VERSION 5.8 ;
BUSBITCHARS "[]" ;
DIVIDERCHAR "/" ;

PROPERTYDEFINITIONS
MACRO RO_tune4 STRING ;
END PROPERTYDEFINITIONS

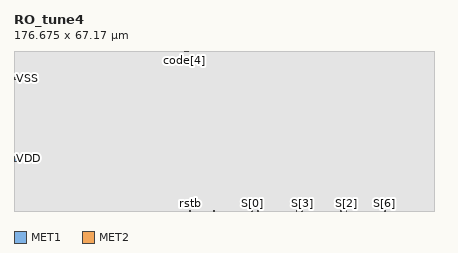
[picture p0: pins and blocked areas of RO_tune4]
MACRO RO_tune4
  CLASS BLOCK ;
  ORIGIN 76.435 85.825 ;
  FOREIGN RO_tune4 -76.435 -85.825 ;
  SIZE 176.675 BY 67.17 ;
  SYMMETRY X Y R90 ;
  PIN code[0]
    DIRECTION INPUT ;
    USE SIGNAL ;
    PORT
      LAYER MET1 ;
        RECT -2.775 -18.885 -2.545 -18.655 ;
    END
  END code[0]
  PIN code[7]
    DIRECTION INPUT ;
    USE SIGNAL ;
    PORT
      LAYER MET1 ;
        RECT -1.805 -18.885 -1.575 -18.655 ;
    END
  END code[7]
  PIN S[0]
    DIRECTION OUTPUT ;
    USE SIGNAL ;
    PORT
      LAYER MET2 ;
        RECT 23.66 -85.825 23.94 -85.545 ;
    END
  END S[0]
  PIN S[7]
    DIRECTION OUTPUT ;
    USE SIGNAL ;
    PORT
      LAYER MET2 ;
        RECT 60.87 -85.825 61.15 -85.545 ;
    END
  END S[7]
  PIN rstb
    DIRECTION INPUT ;
    USE SIGNAL ;
    PORT
      LAYER MET2 ;
        RECT -2.505 -85.825 -2.225 -85.545 ;
    END
  END rstb
  PIN code[1]
    DIRECTION INPUT ;
    USE SIGNAL ;
    PORT
      LAYER MET1 ;
        RECT -3.26 -18.885 -3.03 -18.655 ;
    END
  END code[1]
  PIN code[2]
    DIRECTION INPUT ;
    USE SIGNAL ;
    PORT
      LAYER MET1 ;
        RECT -3.745 -18.885 -3.515 -18.655 ;
    END
  END code[2]
  PIN code[3]
    DIRECTION INPUT ;
    USE SIGNAL ;
    PORT
      LAYER MET1 ;
        RECT -4.23 -18.885 -4 -18.655 ;
    END
  END code[3]
  PIN code[4]
    DIRECTION INPUT ;
    USE SIGNAL ;
    PORT
      LAYER MET1 ;
        RECT -4.715 -18.885 -4.485 -18.655 ;
    END
  END code[4]
  PIN code[5]
    DIRECTION INPUT ;
    USE SIGNAL ;
    PORT
      LAYER MET1 ;
        RECT -5.2 -18.885 -4.97 -18.655 ;
    END
  END code[5]
  PIN code[6]
    DIRECTION INPUT ;
    USE SIGNAL ;
    PORT
      LAYER MET1 ;
        RECT -2.29 -18.885 -2.06 -18.655 ;
    END
  END code[6]
  PIN VDD
    DIRECTION INOUT ;
    USE POWER ;
    PORT
      LAYER MET1 ;
        RECT -76.05 -64.845 -74.06 -62.845 ;
    END
  END VDD
  PIN VSS
    DIRECTION INOUT ;
    USE GROUND ;
    PORT
      LAYER MET1 ;
        RECT -76.215 -30.69 -75.015 -30.43 ;
        RECT -76.215 -30.69 -75.185 -29.67 ;
    END
  END VSS
  PIN S[2]
    DIRECTION OUTPUT ;
    USE SIGNAL ;
    PORT
      LAYER MET2 ;
        RECT 63.25 -85.825 63.53 -85.545 ;
    END
  END S[2]
  PIN S[6]
    DIRECTION OUTPUT ;
    USE SIGNAL ;
    PORT
      LAYER MET2 ;
        RECT 79.475 -85.825 79.755 -85.545 ;
    END
  END S[6]
  PIN S[3]
    DIRECTION OUTPUT ;
    USE SIGNAL ;
    PORT
      LAYER MET2 ;
        RECT 44.645 -85.825 44.925 -85.545 ;
    END
  END S[3]
  PIN S[1]
    DIRECTION OUTPUT ;
    USE SIGNAL ;
    PORT
      LAYER MET2 ;
        RECT 26.04 -85.825 26.32 -85.545 ;
    END
  END S[1]
  PIN S[5]
    DIRECTION OUTPUT ;
    USE SIGNAL ;
    PORT
      LAYER MET2 ;
        RECT 42.265 -85.825 42.545 -85.545 ;
    END
  END S[5]
  PIN S[4]
    DIRECTION OUTPUT ;
    USE SIGNAL ;
    PORT
      LAYER MET2 ;
        RECT 7.435 -85.825 7.715 -85.545 ;
    END
  END S[4]
  PIN vdd!
    DIRECTION INOUT ;
    USE POWER ;
    PORT
      LAYER MET1 ;
        RECT -76.05 -64.845 -74.06 -62.845 ;
    END
  END vdd!
  OBS
    LAYER MET1 ;
      RECT 99.25 -67.175 99.55 -57.125 ;
      RECT 98.13 -67.175 98.43 -57.125 ;
      RECT 97.01 -67.175 97.31 -57.125 ;
      RECT 95.89 -67.175 96.19 -57.125 ;
      RECT 95.76 -67.175 100.24 -66.755 ;
      RECT 99.81 -66.425 100.11 -46.325 ;
      RECT 98.69 -66.425 98.99 -46.325 ;
      RECT 97.57 -66.425 97.87 -46.325 ;
      RECT 96.45 -66.425 96.75 -46.325 ;
      RECT 95.76 -56.795 100.24 -55.955 ;
      RECT 99.25 -55.625 99.55 -35.525 ;
      RECT 98.13 -55.625 98.43 -35.525 ;
      RECT 97.01 -55.625 97.31 -35.525 ;
      RECT 95.89 -55.625 96.19 -35.525 ;
      RECT 95.76 -45.995 100.24 -45.155 ;
      RECT 99.81 -44.825 100.11 -24.725 ;
      RECT 98.69 -44.825 98.99 -24.725 ;
      RECT 97.57 -44.825 97.87 -24.725 ;
      RECT 96.45 -44.825 96.75 -24.725 ;
      RECT 95.76 -35.195 100.24 -34.355 ;
      RECT 95.76 -24.395 100.24 -23.975 ;
      RECT 99.25 -34.025 99.55 -23.975 ;
      RECT 98.13 -34.025 98.43 -23.975 ;
      RECT 97.01 -34.025 97.31 -23.975 ;
      RECT 95.89 -34.025 96.19 -23.975 ;
      RECT -1.805 -60.23 -1.575 -19.485 ;
      RECT -1.83 -60.23 -1.55 -59.85 ;
      RECT -2.29 -55.465 -2.06 -19.485 ;
      RECT -2.315 -55.465 -2.035 -55.085 ;
      RECT -2.775 -50.7 -2.545 -19.485 ;
      RECT -2.8 -50.7 -2.52 -50.32 ;
      RECT -3.26 -45.86 -3.03 -19.485 ;
      RECT -3.285 -45.86 -3.005 -45.48 ;
      RECT -3.745 -41.12 -3.515 -19.485 ;
      RECT -3.77 -41.12 -3.49 -40.74 ;
      RECT -4.23 -36.28 -4 -19.485 ;
      RECT -4.255 -36.28 -3.975 -35.9 ;
      RECT -4.715 -31.515 -4.485 -19.485 ;
      RECT -4.74 -31.515 -4.46 -31.135 ;
      RECT -5.2 -26.725 -4.97 -19.485 ;
      RECT -5.225 -26.725 -4.945 -26.345 ;
      RECT -76.215 -32.35 -75.015 -31.29 ;
      RECT -76.215 -53.845 -75.185 -31.29 ;
      RECT -76.215 -33.49 -22.935 -32.58 ;
      RECT -76.215 -40.685 -21.175 -40.345 ;
      RECT -76.215 -47.265 -21.175 -46.925 ;
      RECT -76.215 -53.845 -21.175 -53.505 ;
      RECT -76.215 -62.09 -75.875 -31.29 ;
      RECT -76.215 -62.09 -5.555 -61.75 ;
      RECT -73.46 -64.845 -0.255 -62.845 ;
      RECT -74.875 -30.2 -48.615 -29.86 ;
      RECT -74.515 -32.35 -74.175 -30.43 ;
    LAYER MET1 SPACING 0.23 ;
      RECT -1.155 -85.825 100.24 -18.655 ;
      RECT -76.435 -29.25 -5.62 -18.655 ;
      RECT -73.64 -85.825 100.24 -19.305 ;
      RECT -74.765 -30.2 100.24 -19.305 ;
      RECT -74.595 -62.425 -5.62 -18.655 ;
      RECT -74.875 -30.2 100.24 -29.86 ;
      RECT -76.435 -62.425 100.24 -31.11 ;
      RECT -76.435 -85.825 100.24 -65.265 ;
    LAYER MET2 ;
      RECT 99.26 -67.175 99.54 -57.125 ;
      RECT 98.14 -67.175 98.42 -57.125 ;
      RECT 97.02 -67.175 97.3 -57.125 ;
      RECT 95.9 -67.175 96.18 -57.125 ;
      RECT 95.76 -67.175 100.24 -66.775 ;
      RECT 99.82 -66.425 100.1 -46.325 ;
      RECT 98.7 -66.425 98.98 -46.325 ;
      RECT 97.58 -66.425 97.86 -46.325 ;
      RECT 96.46 -66.425 96.74 -46.325 ;
      RECT 95.76 -56.775 100.24 -55.975 ;
      RECT 99.26 -55.625 99.54 -35.525 ;
      RECT 98.14 -55.625 98.42 -35.525 ;
      RECT 97.02 -55.625 97.3 -35.525 ;
      RECT 95.9 -55.625 96.18 -35.525 ;
      RECT 95.76 -45.975 100.24 -45.175 ;
      RECT 99.82 -44.825 100.1 -24.725 ;
      RECT 98.7 -44.825 98.98 -24.725 ;
      RECT 97.58 -44.825 97.86 -24.725 ;
      RECT 96.46 -44.825 96.74 -24.725 ;
      RECT 95.76 -35.175 100.24 -34.375 ;
      RECT 95.76 -24.375 100.24 -23.975 ;
      RECT 99.26 -34.025 99.54 -23.975 ;
      RECT 98.14 -34.025 98.42 -23.975 ;
      RECT 97.02 -34.025 97.3 -23.975 ;
      RECT 95.9 -34.025 96.18 -23.975 ;
      RECT 79.445 -84.49 79.785 -80.11 ;
      RECT 79.475 -84.945 79.755 -80.11 ;
      RECT 63.22 -84.49 63.56 -80.11 ;
      RECT 63.25 -84.945 63.53 -80.11 ;
      RECT 60.84 -84.49 61.18 -80.11 ;
      RECT 60.87 -84.945 61.15 -80.11 ;
      RECT 44.615 -84.49 44.955 -80.11 ;
      RECT 44.645 -84.945 44.925 -80.11 ;
      RECT 42.235 -84.49 42.575 -80.11 ;
      RECT 42.265 -84.945 42.545 -80.11 ;
      RECT -31 -22.655 34.925 -18.655 ;
      RECT 30.925 -24.305 34.925 -18.655 ;
      RECT -31 -23.7 -27 -18.655 ;
      RECT 26.01 -84.49 26.35 -80.11 ;
      RECT 26.04 -84.945 26.32 -80.11 ;
      RECT 23.63 -84.49 23.97 -80.11 ;
      RECT 23.66 -84.945 23.94 -80.11 ;
      RECT -2.505 -77.39 12.715 -77.11 ;
      RECT 12.435 -79.025 12.715 -77.11 ;
      RECT -2.505 -84.945 -2.225 -77.11 ;
      RECT -2.59 -83.595 -2.13 -82.095 ;
      RECT 7.405 -84.49 7.745 -80.11 ;
      RECT 7.435 -84.945 7.715 -80.11 ;
      RECT 82.44 -85.55 83.44 -68.935 ;
      RECT -5.12 -85.825 -3.12 -60.855 ;
      RECT -74.515 -44.49 -74.175 -23.065 ;
    LAYER MET2 SPACING 0.28 ;
      RECT -76.435 -29.25 100.24 -18.655 ;
      RECT 80.175 -85.825 100.24 -18.655 ;
      RECT -74.765 -30.01 100.24 -18.655 ;
      RECT -73.64 -85.125 100.24 -18.655 ;
      RECT -74.595 -62.425 100.24 -18.655 ;
      RECT -76.435 -62.425 100.24 -31.11 ;
      RECT -76.435 -85.825 -2.925 -65.265 ;
      RECT 63.95 -85.825 79.055 -18.655 ;
      RECT 61.57 -85.825 62.83 -18.655 ;
      RECT 45.345 -85.825 60.45 -18.655 ;
      RECT 42.965 -85.825 44.225 -18.655 ;
      RECT 26.74 -85.825 41.845 -18.655 ;
      RECT 24.36 -85.825 25.62 -18.655 ;
      RECT 8.135 -85.825 23.24 -18.655 ;
      RECT -1.805 -85.825 7.015 -18.655 ;
    LAYER MET3 ;
      RECT 99.26 -67.175 99.54 -57.325 ;
      RECT 98.14 -67.175 98.42 -57.325 ;
      RECT 97.02 -67.175 97.3 -57.325 ;
      RECT 95.9 -67.175 96.18 -57.325 ;
      RECT 95.76 -67.175 100.24 -66.575 ;
      RECT 99.82 -66.225 100.1 -46.525 ;
      RECT 98.7 -66.225 98.98 -46.525 ;
      RECT 97.58 -66.225 97.86 -46.525 ;
      RECT 96.46 -66.225 96.74 -46.525 ;
      RECT 95.76 -56.975 100.24 -55.775 ;
      RECT 99.26 -55.425 99.54 -35.725 ;
      RECT 98.14 -55.425 98.42 -35.725 ;
      RECT 97.02 -55.425 97.3 -35.725 ;
      RECT 95.9 -55.425 96.18 -35.725 ;
      RECT 95.76 -46.175 100.24 -44.975 ;
      RECT 99.82 -44.625 100.1 -24.925 ;
      RECT 98.7 -44.625 98.98 -24.925 ;
      RECT 97.58 -44.625 97.86 -24.925 ;
      RECT 96.46 -44.625 96.74 -24.925 ;
      RECT 95.76 -35.375 100.24 -34.175 ;
      RECT 95.76 -24.575 100.24 -23.975 ;
      RECT 99.26 -33.825 99.54 -23.975 ;
      RECT 98.14 -33.825 98.42 -23.975 ;
      RECT 97.02 -33.825 97.3 -23.975 ;
      RECT 95.9 -33.825 96.18 -23.975 ;
    LAYER MET3 SPACING 0.28 ;
      RECT -76.435 -85.125 100.24 -18.655 ;
      RECT 80.175 -85.825 100.24 -18.655 ;
      RECT 63.95 -85.825 79.055 -18.655 ;
      RECT 61.57 -85.825 62.83 -18.655 ;
      RECT 45.345 -85.825 60.45 -18.655 ;
      RECT 42.965 -85.825 44.225 -18.655 ;
      RECT 26.74 -85.825 41.845 -18.655 ;
      RECT 24.36 -85.825 25.62 -18.655 ;
      RECT 8.135 -85.825 23.24 -18.655 ;
      RECT -1.805 -85.825 7.015 -18.655 ;
      RECT -76.435 -85.825 -2.925 -18.655 ;
    LAYER METTP SPACING 0.46 ;
      RECT -76.435 -85.825 100.24 -18.655 ;
  END
  PROPERTY CatenaDesignType "mixed" ;
END RO_tune4

END LIBRARY
